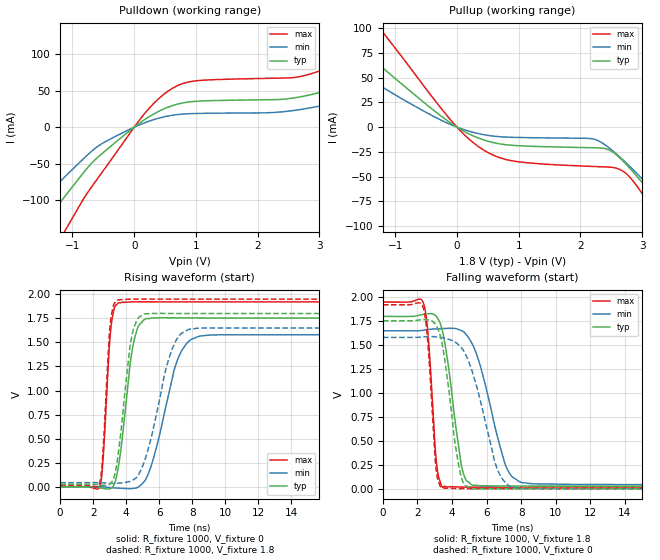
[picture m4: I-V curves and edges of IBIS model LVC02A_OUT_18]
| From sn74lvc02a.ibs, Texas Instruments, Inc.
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[Model]   LVC02A_OUT_18
Model_type  Output
Vref =   0
Rref =   1000
Cref =   30p
Vmeas =   0.9
| variable   typ   min   max
C_comp   8.01pF   4.11pF   12.98pF
| C_pullup   7.12pF   4.11pF   8.72pF
| C_pulldown   8.89pF   4.62pF   12.98pF
[Temperature Range]   40   100   -40
| Ambient temperature   25   85   -40
[Voltage range]   1.8   1.65   1.95
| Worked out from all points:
|   slope of the pulldown table from 0 to 0.27 V, typ, clamps not added: 17.1 ohm
|   slope of the pullup table from 0 to 0.27 V, typ, clamps not added: 29.9 ohm
|   rising waveform, R_fixture 1000, V_fixture 0: 20-80 % time 699ps typ, 1.32ns min, 376ps max; typ from 0 V to 1.75 V
|   falling waveform, R_fixture 1000, V_fixture 1.8: 20-80 % time 775ps typ, 1.34ns min, 400ps max; typ from 1.8 V to 0.027 V
|   rising waveform, R_fixture 1000, V_fixture 1.8: 20-80 % time 675ps typ, 1.3ns min, 366ps max; typ from 0.027 V to 1.8 V
|   falling waveform, R_fixture 1000, V_fixture 0: 20-80 % time 751ps typ, 1.33ns min, 404ps max; typ from 1.75 V to 0 V
[Pulldown]
| LVC02A_OUT_18
|   Voltage   I(typ)   I(min)   I(max)
-5.5V     -559.1mA   -452.2mA   -710.9mA
-2.18V    -208.5mA   -158.8mA   -285.4mA
-1.865V   -175.2mA   -131.6mA   -244.5mA
-1.48V    -133.9mA   -98.56mA   -193.1mA
-1.07V    -89.31mA   -63.76mA   -134.9mA
70mV      4.491mA    2.617mA    8.125mA
615mV     29.45mA    16.27mA    53.12mA
2.815V    43.69mA    25.92mA    72.1mA
4.325V    93.52mA    64.21mA    142.7mA
5.155V    134.5mA    96.03mA    199.6mA
6.155V    191.3mA    141.3mA    276.1mA
11V       510.2mA    405.2mA    689.3mA
[Pullup]
| LVC02A_OUT_18
|   Voltage   I(typ)   I(min)   I(max)
-5.5V     324.9mA    249.5mA    454.8mA
-2.68V    143.9mA    103mA      216.3mA
-2.015V   104.9mA    73.15mA    161.8mA
-1.32V    66.21mA    44.72mA    105.6mA
360mV     -11.3mA    -6.711mA   -20.18mA
985mV     -18.72mA   -10.42mA   -34.9mA
2.465V    -23.02mA   -20.97mA   -40.36mA
2.785V    -40.46mA   -38.76mA   -49.43mA
3.365V    -85.63mA   -77.45mA   -103.2mA
3.56V     -102.6mA   -91.66mA   -124.4mA
3.775V    -122mA     -107.8mA   -148.7mA
11V       -874.4mA   -739.7mA   -1.068A
[Ramp]
| LVC02A_OUT_18
| variable   typ   min   max
dV/dt_r   1.07/7.55E-10   0.96/1.38E-09   1.17/4.04E-10
dV/dt_f   1.08/8.10E-10   0.98/1.41E-09   1.18/4.18E-10
R_load = 1000
[Rising Waveform]
| LVC02A_OUT_18
R_fixture =   1000
C_fixture =   0
L_fixture =   0
V_fixture =   0
V_fixture_min = 0
V_fixture_max = 0
|   Time   V(typ)   V(min)   V(max)
0s        194.2pV    4.892nV    16.26pV
2.41ns    -10.71mV   15.91uV    7.209mV
2.605ns   -17.12mV   -1.09mV    292.5mV
3.07ns    -17.58mV   -9.555mV   1.64V
3.545ns   224.9mV    -14.86mV   1.912V
4.405ns   1.455V     -18.34mV   1.921V
5.18ns    1.745V     72.89mV    1.922V
7.005ns   1.756V     1.264V     1.922V
7.995ns   1.754V     1.536V     1.922V
24.99ns   1.754V     1.581V     1.922V
[Falling Waveform]
| LVC02A_OUT_18
R_fixture =   1000
C_fixture =   0
L_fixture =   0
V_fixture =   1.8
V_fixture_min = 1.65
V_fixture_max = 1.95
|   Time   V(typ)   V(min)   V(max)
0s        1.8V       1.65V      1.95V
2.355ns   1.822V     1.656V     1.935V
2.62ns    1.827V     1.663V     1.598V
3.095ns   1.8V       1.67V      284.1mV
3.465ns   1.63V      1.673V     16.05mV
4.54ns    244.7mV    1.652V     16.81mV
5.18ns    36.44mV    1.509V     15.82mV
7.07ns    27.63mV    256.7mV    16.24mV
7.96ns    27.2mV     68.51mV    16.27mV
24.99ns   27.13mV    42.42mV    16.27mV
[Rising Waveform]
| LVC02A_OUT_18
R_fixture =   1000
C_fixture =   0
L_fixture =   0
V_fixture =   1.8
V_fixture_min = 1.65
V_fixture_max = 1.95
|   Time   V(typ)   V(min)   V(max)
0s        27.13mV    42.42mV    16.27mV
2.41ns    18.31mV    42.29mV    45.1mV
2.59ns    15.12mV    41.41mV    348.9mV
3.03ns    29.26mV    35.42mV    1.673V
3.485ns   296.5mV    36.52mV    1.941V
4.31ns    1.534V     61.24mV    1.95V
5.085ns   1.794V     253.8mV    1.951V
6.665ns   1.801V     1.369V     1.95V
7.765ns   1.8V       1.633V     1.95V
24.99ns   1.8V       1.65V      1.95V
[Falling Waveform]
| LVC02A_OUT_18
R_fixture =   1000
C_fixture =   0
L_fixture =   0
V_fixture =   0
V_fixture_min = 0
V_fixture_max = 0
|   Time   V(typ)   V(min)   V(max)
0s        1.754V     1.581V     1.922V
2.35ns    1.767V     1.586V     1.882V
2.605ns   1.764V     1.59V      1.519V
3.055ns   1.716V     1.586V     250.1mV
3.395ns   1.541V     1.578V     6.528mV
4.435ns   200.3mV    1.493V     546.2uV
5.085ns   -1.025mV   1.269V     -497.9uV
6.515ns   248.9uV    257.1mV    -80.22uV
7.45ns    1.191uV    15.14mV    -1.865uV
24.99ns   -23.11nV   15.54nV    -774.8pV
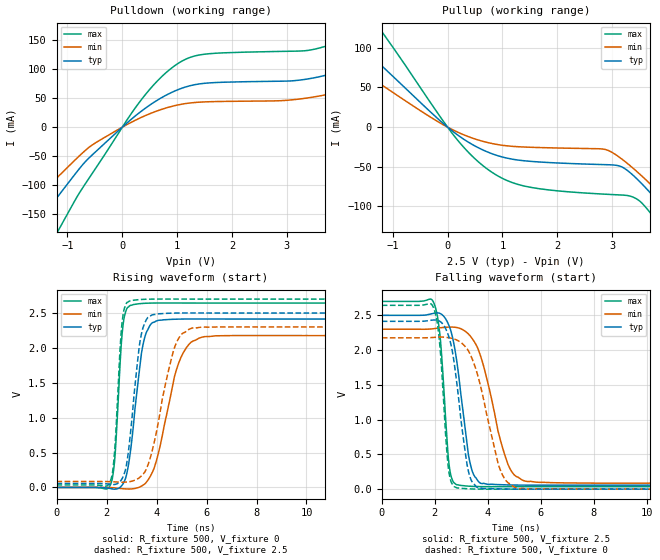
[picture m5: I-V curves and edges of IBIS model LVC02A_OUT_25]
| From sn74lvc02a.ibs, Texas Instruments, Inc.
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[Model]   LVC02A_OUT_25
Model_type  Output
Vref =   0
Rref =   500
Cref =   30p
Vmeas =   1.25
| variable   typ   min   max
C_comp   7.77pF   3.92pF   12.04pF
| C_pullup   7.17pF   3.92pF   8.67pF
| C_pulldown   8.37pF   4.36pF   12.04pF
[Temperature Range]   40   100   -40
| Ambient temperature   25   85   -40
[Voltage range]   2.5   2.3   2.7
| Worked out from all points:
|   slope of the pulldown table from 0 to 0.375 V, typ, clamps not added: 12.7 ohm
|   slope of the pullup table from 0 to 0.375 V, typ, clamps not added: 20 ohm
|   rising waveform, R_fixture 500, V_fixture 0: 20-80 % time 457ps typ, 810ps min, 249ps max; typ from 0 V to 2.41 V
|   falling waveform, R_fixture 500, V_fixture 2.5: 20-80 % time 493ps typ, 837ps min, 281ps max; typ from 2.5 V to 0.057 V
|   rising waveform, R_fixture 500, V_fixture 2.5: 20-80 % time 420ps typ, 776ps min, 241ps max; typ from 0.057 V to 2.5 V
|   falling waveform, R_fixture 500, V_fixture 0: 20-80 % time 482ps typ, 811ps min, 279ps max; typ from 2.41 V to 0 V
[Pulldown]
| LVC02A_OUT_25
|   Voltage   I(typ)   I(min)   I(max)
-5.5V     -598.1mA   -479.8mA   -766.5mA
-2.12V    -233mA     -174.4mA   -327.1mA
-1.575V   -168.1mA   -123.2mA   -244.7mA
-1.15V    -116.2mA   -83.21mA   -174.9mA
-565mV    -49.19mA   -31.72mA   -81.94mA
365mV     28.75mA    17.58mA    49.46mA
1.32V     73.05mA    42.4mA     122.5mA
4V        96.78mA    61.72mA    149.2mA
4.6V      117.3mA    77.78mA    177.9mA
5.77V     171.8mA    120.4mA    253.2mA
7.055V    245.3mA    179.5mA    351.5mA
11V       504.9mA    394.6mA    686.5mA
[Pullup]
| LVC02A_OUT_25
|   Voltage   I(typ)   I(min)   I(max)
-5.5V     363.4mA    279.9mA    508.8mA
-2.6V     169.4mA    122.6mA    251.6mA
-1.815V   117.7mA    83.03mA    179.1mA
-1.37V    88.47mA    61.37mA    136.9mA
170mV     -9.222mA   -5.867mA   -15.32mA
760mV     -32.2mA    -19.89mA   -54.58mA
2.905V    -47.35mA   -28.79mA   -84.65mA
3.45V     -65.04mA   -55.88mA   -90.57mA
3.92V     -100.7mA   -87.07mA   -129.3mA
4.19V     -123.8mA   -106.6mA   -157.6mA
4.495V    -151.4mA   -129.7mA   -191.8mA
11V       -830.2mA   -699.2mA   -1.022A
[Ramp]
| LVC02A_OUT_25
| variable   typ   min   max
dV/dt_r   1.46/4.68E-10   1.32/8.88E-10   1.60/2.61E-10
dV/dt_f   1.49/5.08E-10   1.35/8.91E-10   1.62/2.88E-10
R_load = 500
[Rising Waveform]
| LVC02A_OUT_25
R_fixture =   500
C_fixture =   0
L_fixture =   0
V_fixture =   0
V_fixture_min = 0
V_fixture_max = 0
|   Time   V(typ)   V(min)   V(max)
0s        177.7pV    3.876nV    17.91pV
2.16ns    -16.72mV   -2.452mV   40.07mV
2.335ns   -24.71mV   -6.902mV   433.8mV
2.645ns   43.9mV     -17.85mV   2.275V
2.965ns   537.9mV    -21.76mV   2.611V
3.395ns   1.917V     18.35mV    2.637V
3.715ns   2.309V     138mV      2.642V
4.9ns     2.413V     1.796V     2.644V
5.815ns   2.415V     2.154V     2.644V
24.99ns   2.414V     2.176V     2.644V
[Falling Waveform]
| LVC02A_OUT_25
R_fixture =   500
C_fixture =   0
L_fixture =   0
V_fixture =   2.5
V_fixture_min = 2.3
V_fixture_max = 2.7
|   Time   V(typ)   V(min)   V(max)
0s        2.5V       2.3V       2.7V
1.97ns    2.53V      2.308V     2.672V
2.2ns     2.527V     2.321V     2.189V
2.545ns   2.341V     2.33V      327.9mV
2.83ns    1.834V     2.324V     63.05mV
3.265ns   497.3mV    2.233V     42.8mV
3.48ns    195.4mV    2.124V     38.46mV
4.76ns    60.67mV    354.3mV    35.41mV
5.405ns   57.49mV    115mV      35.78mV
24.99ns   57.33mV    84.96mV    35.94mV
[Rising Waveform]
| LVC02A_OUT_25
R_fixture =   500
C_fixture =   0
L_fixture =   0
V_fixture =   2.5
V_fixture_min = 2.3
V_fixture_max = 2.7
|   Time   V(typ)   V(min)   V(max)
0s        57.33mV    84.96mV    35.94mV
2.155ns   44.81mV    83.06mV    90.02mV
2.32ns    42.67mV    80.2mV     500.2mV
2.625ns   127.2mV    75.25mV    2.372V
2.94ns    717.3mV    84.02mV    2.675V
3.31ns    2.023V     138.3mV    2.693V
3.58ns    2.396V     254.3mV    2.698V
4.69ns    2.499V     1.976V     2.7V
5.41ns    2.501V     2.284V     2.7V
24.99ns   2.5V       2.3V       2.7V
[Falling Waveform]
| LVC02A_OUT_25
R_fixture =   500
C_fixture =   0
L_fixture =   0
V_fixture =   0
V_fixture_min = 0
V_fixture_max = 0
|   Time   V(typ)   V(min)   V(max)
0s        2.414V     2.176V     2.644V
1.95ns    2.432V     2.182V     2.611V
2.18ns    2.416V     2.188V     2.103V
2.515ns   2.207V     2.178V     290.5mV
2.83ns    1.523V     2.144V     18.04mV
3.22ns    340.5mV    2.015V     5.575mV
3.395ns   111.2mV    1.885V     2.73mV
4.41ns    3.812mV    335.8mV    -642.7uV
5.11ns    -46.03uV   11.28mV    -233.2uV
24.99ns   11.32nV    12.41nV    6.539nV
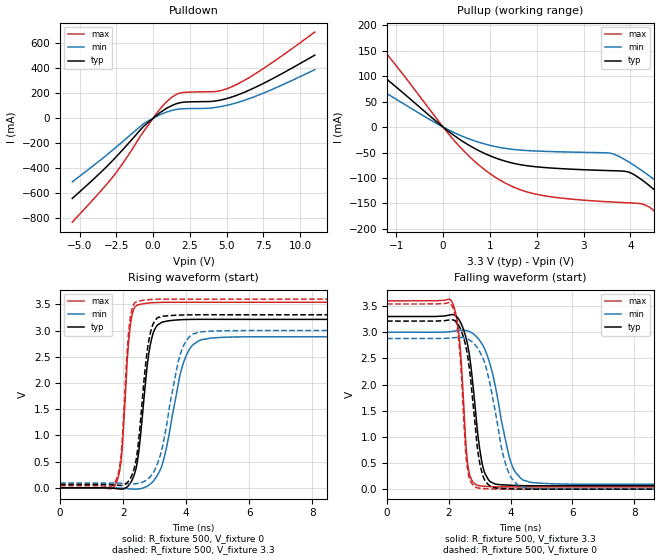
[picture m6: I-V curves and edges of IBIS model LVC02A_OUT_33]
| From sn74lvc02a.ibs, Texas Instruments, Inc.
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[Model]   LVC02A_OUT_33
Model_type  Output
Vref =   0
Rref =   500
Cref =   50p
Vmeas =   1.5
| variable   typ   min   max
C_comp   7.47pF   3.90pF   11.10pF
| C_pullup   7.19pF   3.90pF   8.99pF
| C_pulldown   7.75pF   4.16pF   11.10pF
[Temperature Range]   40   100   -40
| Ambient temperature   25   85   -40
[Voltage range]   3.3   3   3.6
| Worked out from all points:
|   slope of the pulldown table from 0 to 0.495 V, typ, clamps not added: 10.7 ohm
|   slope of the pullup table from 0 to 0.495 V, typ, clamps not added: 15.2 ohm
|   rising waveform, R_fixture 500, V_fixture 0: 20-80 % time 332ps typ, 573ps min, 219ps max; typ from 0 V to 3.21 V
|   falling waveform, R_fixture 500, V_fixture 3.3: 20-80 % time 373ps typ, 616ps min, 227ps max; typ from 3.3 V to 0.065 V
|   rising waveform, R_fixture 500, V_fixture 3.3: 20-80 % time 318ps typ, 549ps min, 212ps max; typ from 0.065 V to 3.3 V
|   falling waveform, R_fixture 500, V_fixture 0: 20-80 % time 358ps typ, 578ps min, 224ps max; typ from 3.21 V to 0 V
[Pulldown]
| LVC02A_OUT_33
|   Voltage   I(typ)   I(min)   I(max)
-5.5V     -642.1mA   -509.2mA   -832.1mA
-3.645V   -442.6mA   -340.3mA   -594.1mA
-2.71V    -333.2mA   -250.5mA   -464.6mA
-1.885V   -228.4mA   -168.1mA   -330.7mA
-620mV    -62.4mA    -41.49mA   -102.1mA
455mV     42.83mA    26.93mA    71.74mA
1.215V    98.07mA    60.46mA    162.3mA
1.91V     125.9mA    75.23mA    203.5mA
4.31V     139.6mA    87.57mA    214.6mA
5.45V     173.8mA    116.3mA    257.3mA
7.53V     280.4mA    202.4mA    399.9mA
11V       505.3mA    389mA      689.8mA
[Pullup]
| LVC02A_OUT_33
|   Voltage   I(typ)   I(min)   I(max)
-5.5V     404.4mA    310.8mA    569.2mA
-3.515V   265mA      197.3mA    383.4mA
-2.48V    190.1mA    138.3mA    280.1mA
-1.635V   127.1mA    90.28mA    191.1mA
505mV     -33.05mA   -21.44mA   -52.79mA
1.855V    -76.61mA   -46.34mA   -128.9mA
3.7V      -85.85mA   -55.1mA    -147.6mA
4.24V     -103.3mA   -84.95mA   -151mA
4.895V    -154.7mA   -130.6mA   -201.2mA
5.365V    -197.4mA   -166.8mA   -253mA
5.825V    -241.6mA   -203.9mA   -307.6mA
11V       -786.6mA   -661.2mA   -974mA
[Ramp]
| LVC02A_OUT_33
| variable   typ   min   max
dV/dt_r   1.94/3.50E-10   1.74/6.23E-10   2.14/2.32E-10
dV/dt_f   1.96/3.90E-10   1.77/6.48E-10   2.16/2.35E-10
R_load = 500
[Rising Waveform]
| LVC02A_OUT_33
R_fixture =   500
C_fixture =   0
L_fixture =   0
V_fixture =   0
V_fixture_min = 0
V_fixture_max = 0
|   Time   V(typ)   V(min)   V(max)
0s        184.9pV    3.596nV    21.02pV
1.79ns    -14.31mV   -1.603mV   108.6mV
1.95ns    -24.66mV   -6.205mV   605.5mV
2.225ns   86.33mV    -20.46mV   3.078V
2.475ns   597.3mV    -22.24mV   3.492V
2.78ns    2.409V     37.7mV     3.523V
2.99ns    3.007V     151.5mV    3.532V
3.925ns   3.209V     2.402V     3.54V
4.515ns   3.213V     2.83V      3.539V
24.99ns   3.212V     2.88V      3.539V
[Falling Waveform]
| LVC02A_OUT_33
R_fixture =   500
C_fixture =   0
L_fixture =   0
V_fixture =   3.3
V_fixture_min = 3
V_fixture_max = 3.6
|   Time   V(typ)   V(min)   V(max)
0s        3.3V       3V         3.6V
2.11ns    3.337V     3.016V     3.571V
2.35ns    3.219V     3.035V     2.823V
2.615ns   2.735V     3.023V     460.7mV
2.955ns   960.9mV    2.875V     67.74mV
3.105ns   420.1mV    2.743V     56.67mV
3.285ns   177.3mV    2.479V     49.71mV
4.02ns    73.83mV    491.6mV    41.65mV
4.64ns    64.74mV    130mV      41.68mV
24.99ns   64.52mV    92.1mV     41.93mV
[Rising Waveform]
| LVC02A_OUT_33
R_fixture =   500
C_fixture =   0
L_fixture =   0
V_fixture =   3.3
V_fixture_min = 3
V_fixture_max = 3.6
|   Time   V(typ)   V(min)   V(max)
0s        64.52mV    92.1mV     41.93mV
1.78ns    53.07mV    90.69mV    150.2mV
1.94ns    45.68mV    87.02mV    662.5mV
2.21ns    162.2mV    77.46mV    3.165V
2.475ns   809.8mV    84.91mV    3.559V
2.755ns   2.57V      155.9mV    3.585V
2.955ns   3.129V     284mV      3.594V
3.825ns   3.295V     2.566V     3.6V
4.42ns    3.301V     2.972V     3.6V
24.99ns   3.3V       3V         3.6V
[Falling Waveform]
| LVC02A_OUT_33
R_fixture =   500
C_fixture =   0
L_fixture =   0
V_fixture =   0
V_fixture_min = 0
V_fixture_max = 0
|   Time   V(typ)   V(min)   V(max)
0s        3.212V     2.88V      3.539V
2.1ns     3.238V     2.891V     3.51V
2.33ns    3.118V     2.9V       2.787V
2.53ns    2.78V      2.885V     843.9mV
2.6ns     2.572V     2.871V     395.9mV
2.93ns    760.5mV    2.695V     23.71mV
3.18ns    155.9mV    2.373V     9.767mV
3.89ns    8.138mV    383.8mV    -47.11uV
4.505ns   241.5uV    22.97mV    -297.2uV
24.99ns   11.34nV    10.63nV    6.31nV
